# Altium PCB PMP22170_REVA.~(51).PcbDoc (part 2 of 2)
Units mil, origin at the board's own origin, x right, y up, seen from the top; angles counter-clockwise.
Board outline 4950 x 3450 mil, 2 copper layers (Top Layer, Bottom Layer), stack 62 mil thick; 75 components, 28 nets, 160 pads, 117 vias.
Unrouted connection lines stored in the file: 141.

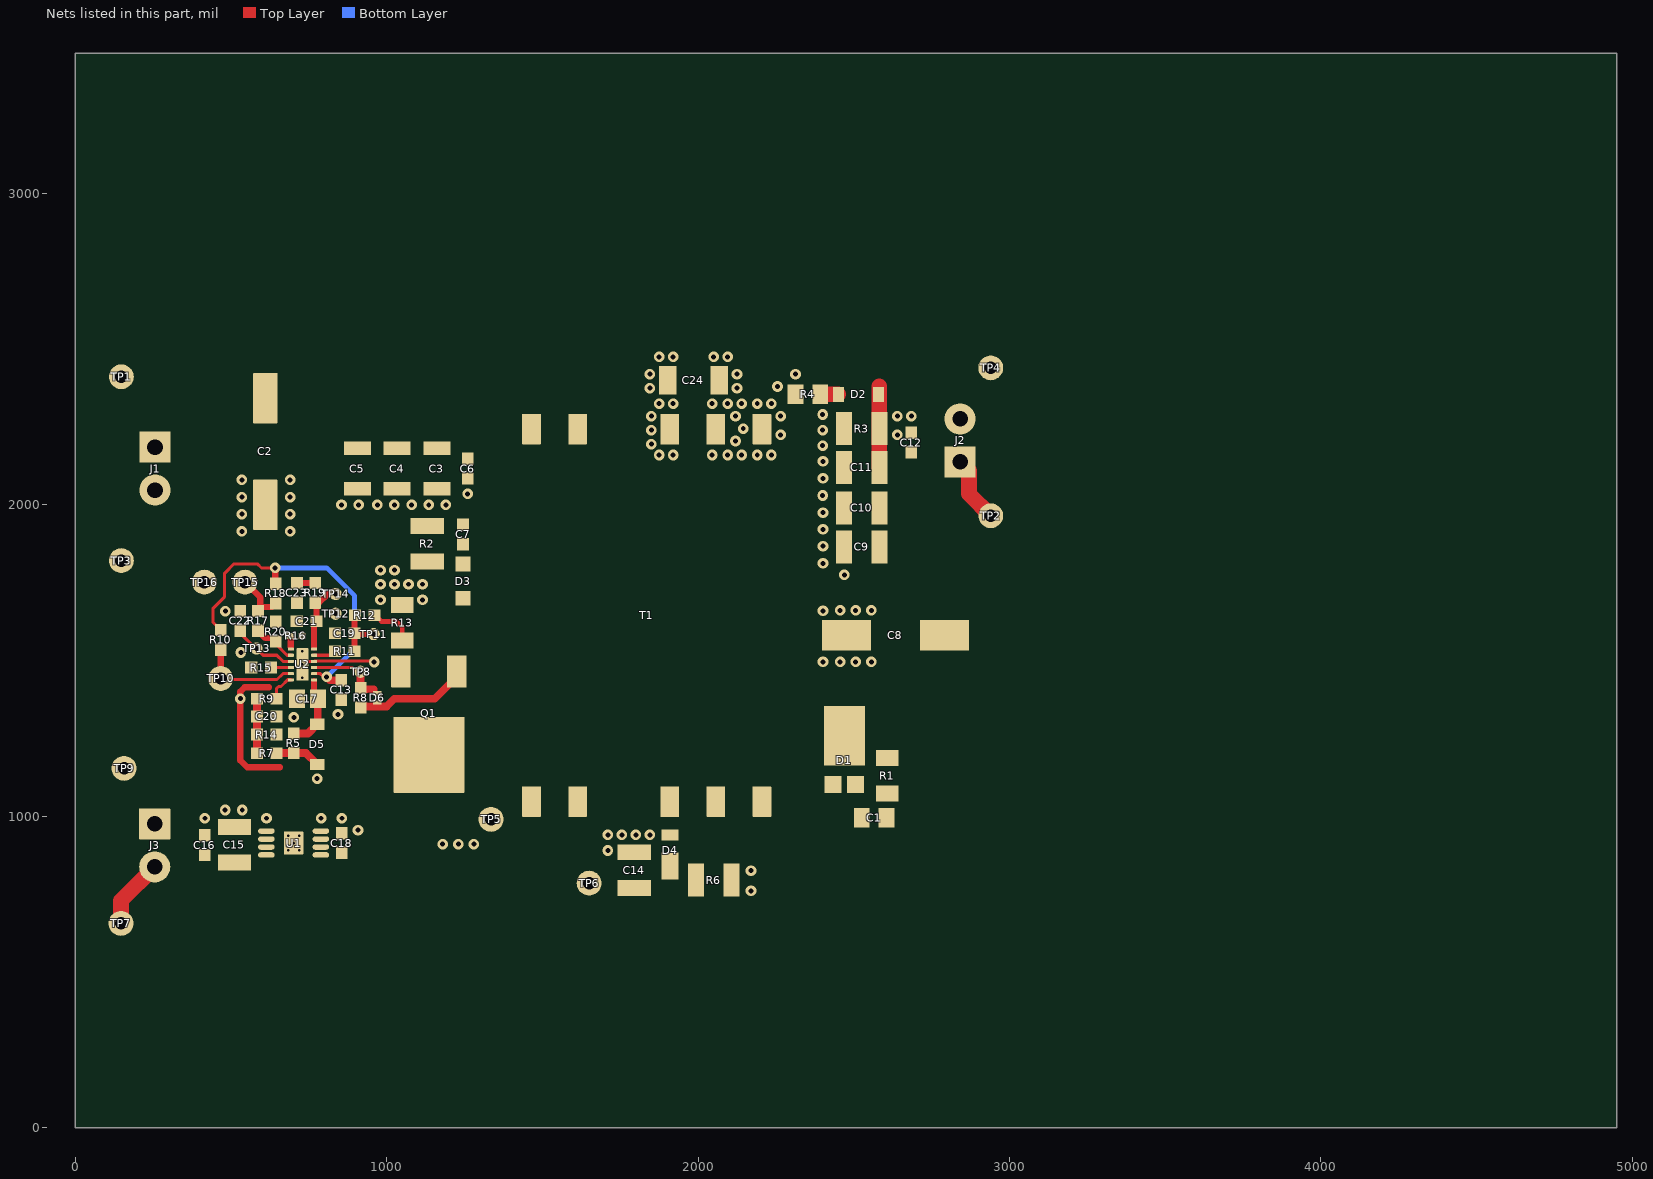
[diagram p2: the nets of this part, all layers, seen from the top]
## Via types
v1: diameter 34, hole 16, Top Layer to Bottom Layer, 109 vias
v2: diameter 19.68, hole 7.87, Top Layer to Bottom Layer, 8 vias

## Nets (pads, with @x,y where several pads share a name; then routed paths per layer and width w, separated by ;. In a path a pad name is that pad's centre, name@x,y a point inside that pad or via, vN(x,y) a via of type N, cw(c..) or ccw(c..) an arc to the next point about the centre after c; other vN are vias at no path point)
GND: C2.1 C3.2 C4.2 C5.2 C6.2 C13.2 C14.2 C15.2 C16.2 C17.2 C18.2 C19.2 C20.2 C21.2 C22.2 C23.2 C24.2 J1.2 J3.1 R6.1 R13.1 R14.1 R15.1 R16.1 R20.1 T1.9 TP3.1 TP9.1 TP12.1 TP16.1 U1.3 U1.4 U1.5 U1.6 U1.7 U1.9 U2.4 U2.13@729.43,1487.34 | length 690.3
  Top Layer w10: v2(729.43,1487.34) 739.27,1497.18 U2.4@766.83,1497.18 767.74,1498.08 956.73,1498.08 v1(959.45,1495.37)
  Top Layer w20: 621.83,1413.91 543.43,1413.91 529.91,1400.39 v1(529.91,1377.34) 529.91,1179.26 551.83,1157.34 656.83,1157.34
  other v1: 2170,760 2170,825 1710,890 1179.41,910 1230,910 1280,910 1710,940 1755,940.2 1800,940 1845,940 907.8,955.27 416.04,993.46 613.93,993.46 789.11,993.46 856.04,993.46 481.04,1020.03 536.04,1020.03 701.83,1317.34 843.57,1327.34 531.83,1525.84 835.75,1650.37 481.83,1658.71 980,1695 1115,1695 980,1745 1025,1745 1070,1745 1115,1745 980,1790 1025,1790 535,1915 690,1915 535,1970 690,1970 854.76,1999.87 909.76,1999.87 969.76,1999.87 1024.76,1999.87 1080,1999.87 1135,1999.87 1189.76,1999.87 535,2025 690,2025 1260,2035 535,2080 690,2080 1875,2160 1920,2160 1850,2195 1850,2240 1850,2285 1875,2325 1920,2325 1845,2375 1845,2420 1875,2475 1920,2475
  other v2: 683.33,890.27 718.76,890.27 701.04,913.89 683.33,937.51 718.76,937.51 729.43,1445.01 729.43,1529.66
GND2: C8.2 C9.2 C10.2 C11.2 C12.2 C24.1 J2.2 R3.1 R4.1 T1.7 T1.8 TP4.1
  other v1: 2401.22,1495.81 2456.22,1495.81 2506.22,1495.81 2556.22,1495.81 2401.22,1659.59 2456.22,1660.81 2506.22,1660.81 2556.22,1660.81 2470,1775 2401.22,1812.32 2401.22,1867.32 2401.22,1921.14 2401.22,1975 2400,2030 2401.22,2085.24 2401.22,2139.68 2045,2160 2095,2160 2140,2160 2190,2160 2235,2160 2400,2190 2120,2205 2265,2225 2640,2225 2400,2240 2145,2245 2120,2284.96 2265,2285 2640,2284.96 2685,2285 2400,2290 2045,2325 2095,2325 2140,2325 2190,2325 2235,2325 2125,2375 2255,2380 2125,2420 2312.77,2420 2050,2475 2095,2475
NetC1_1: C1.1 R1.1
NetC1_2: C1.2 D1.1 D1.2 T1.5 T1.6
NetC2_2: C2.2 C3.1 C4.1 C5.1 C6.1 C7.1 D5.2 J1.1 R2.2 R5.2 R7.2 T1.11 T1.12 TP1.1 | length 145.7
  Top Layer w25: R7.2@646.28,1202.3 646.64,1202.65 R5.2@701.83,1202.65 740.55,1202.65 D5.2@776.83,1166.37
  other v1: 776.83,1120.37
NetC7_2: C7.2 D3.1 R2.1
NetC8_1: C8.1 C9.1 C10.1 C11.1 C12.1 D1.3 D2.1 J2.1 R1.2 R3.2 TP2.1 | length 473.7
  Top Layer w50: C11.1@2582.09,2120 2582.09,2380 ; J2.1@2841.5,2137.89 2870,2109.39 2870,2035 TP2.1@2940,1965
NetC13_1: C13.1 C14.1 C18.1 D4.1 R6.2 R10.1 R18.2 TP6.1 U1.1 U1.2 U2.2 | length 1125.5
  Top Layer w10: R10.1@466.83,1597.69 442.5,1622.02 442.5,1668.42 479.45,1705.37 479.45,1780.37 509.45,1810.37 584.6,1810.37 597.63,1797.34 v1(641.83,1797.34) ; U2.2@766.83,1457.81 786.89,1457.81 797.36,1447.34 v1(806.83,1447.34)
  Top Layer w20: v1(641.83,1797.34) 641.83,1748.38 R18.2@643.33,1746.88
  Top Layer w25: v1(806.83,1447.34) 817.31,1436.86 C13.1@854.45,1436.86
  Bottom Layer w15: v1(641.83,1797.34) 807.48,1797.34 896.71,1708.1 896.71,1537.22 v1(806.83,1447.34)
NetC15_1: C15.1 C16.1 J3.2 TP7.1 U1.8 | length 226.4
  Top Layer w50: TP7.1@146.59,655.86 146.59,729.14 J3.2@254.86,837.41
NetC17_1: C17.1 D5.1 R5.1 U2.1 | length 235.8
  Top Layer w10: 766.83,1432.34 U2.1@766.83,1438.12
  Top Layer w20: 766.83,1432.34 766.83,1389.23 C17.1@778.76,1377.3
  Top Layer w25: R5.1@701.83,1265.64 747.17,1265.64 D5.1@776.83,1295.31 778.76,1297.24 C17.1@778.76,1377.3
NetC19_1: C19.1 R11.2 R12.1 TP11.1 | length 178.8
  Top Layer w20: R11.2@896.71,1529.66 C19.1@896.71,1587.34 ; R12.1@897.95,1645.37 896.71,1644.13 C19.1@896.71,1587.34 ; v1(958.29,1584.89) 899.16,1584.89 C19.1@896.71,1587.34
NetC20_1: C20.1 R7.1 R9.1 R14.2 | length 175
  Top Layer w25: R7.1@583.29,1202.3 C20.1@583.29,1320.34 R9.1@583.29,1377.34
NetC21_1: C21.1 R19.2 TP14.1 U2.6 | length 231
  Top Layer w10: U2.6@766.83,1536.55 766.83,1544.42
  Top Layer w20: 766.83,1544.42 766.83,1618.34 C21.1@774.33,1625.84 774.33,1681.84 R19.2@770.34,1685.84 782.38,1685.84 810.24,1713.7 v1(835.75,1713.7)
NetC22_1: C22.1 TP13.1 U2.9 | length 207.4
  Top Layer w10: C22.1@529.91,1595.72 529.91,1588.12 579.39,1538.63 v1(581.83,1538.63) 603.6,1516.86 647.03,1516.86 666.71,1497.18 U2.9@692.03,1497.18
NetC23_1: C23.1 R19.1 | length 58.5
  Top Layer w20: C23.1@711.83,1748.83 R19.1@770.34,1748.83
NetD2_2: D2.2 R4.2 | length 57.9
  Top Layer w50: R4.2@2392.77,2355 D2.2@2450.7,2355
NetD3_2: D3.2 Q1.2 T1.1 T1.2 TP5.1
NetD4_2: D4.2 T1.4
NetD6_1: D6.1 R8.2 TP8.1 U2.3 | length 265.8
  Top Layer w10: U2.3@766.83,1477.49 889.59,1477.49 903.17,1463.91 v1(915.97,1463.91)
  Top Layer w15: 958.29,1407.93 D6.1@967.65,1395.27
  Top Layer w25: v1(915.97,1463.91) 915.97,1413.02 R8.2@917.13,1411.86 921.07,1407.93 958.29,1407.93
NetD6_2: D6.2 Q1.1 R8.1 | length 366
  Top Layer w25: R8.1@917.13,1348.87 921.07,1352.81 1000.24,1352.81 1024.72,1377.3 1154.41,1377.3 1225.12,1448 Q1.1@1225.12,1464.97
NetQ1_3: Q1.3 R12.2 R13.2 | length 148.1
  Top Layer w15: R12.2@960.95,1645.37 970.95,1635.37 973.35,1635.37 983.35,1625.37 1032.43,1625.37 1049.45,1608.34 R13.2@1049.45,1564.09
NetR9_2: R9.2 U2.12 | length 90.3
  Top Layer w10: R9.2@646.28,1377.34 646.28,1410.45 652.5,1416.67 660.4,1416.67 681.85,1438.12 U2.12@692.03,1438.12
NetR11_1: R11.1 U2.5 | length 72.2
  Top Layer w10: U2.5@766.83,1516.86 820.93,1516.86 R11.1@833.72,1529.66
NetR15_2: R15.2 U2.10 | length 63.7
  Top Layer w10: R15.2@628.33,1477.49 U2.10@692.03,1477.49
NetR16_2: R16.2 U2.7 | length 43.8
  Top Layer w10: U2.7@692.03,1536.55 692.03,1544.41
  Top Layer w20: R16.2@688.7,1578.99 692.03,1575.66 692.03,1544.41
NetR17_1: R17.1 R18.1 TP15.1 | length 169.3
  Top Layer w20: TP15.1@544.9,1751.78 593.9,1702.79 593.9,1678.77 R17.1@600.34,1672.34 ; R17.1@586.83,1658.83 R17.1@600.34,1672.34 ; R18.1@643.33,1683.89 631.77,1672.34 R17.1@600.34,1672.34
NetR17_2: R17.2 R20.2 U2.8 | length 142.5
  Top Layer w10: R20.2@643.33,1561.27 643.33,1553.43 679.9,1516.86 U2.8@692.03,1516.86
  Top Layer w20: R17.2@586.83,1595.84 610.34,1572.34 632.27,1572.34 R20.2@643.33,1561.27
PG: R10.2 TP10.1 U2.11 | length 326.8
  Top Layer w10: TP10.1@466.83,1442.34 470.3,1438.87 647.78,1438.87 666.71,1457.81 U2.11@692.03,1457.81
  Top Layer w20: TP10.1@466.83,1442.34 R10.2@466.83,1534.7
pads on no net: U2.13@729.43,1460.37 U2.13@729.43,1514.3

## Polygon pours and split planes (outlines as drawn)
NetC8_1 on Top Layer "TOP_LAYER_NETC8_1_P046" (solid, remove dead copper, pour order 46): 2401.22,1160 2405,1163.78 2405,1430 2435,1460 2565.83,1460 2594.61,1488.78 2595,1671.22 2556.22,1710 2556.22,2163.54 2582.68,2190 2641.65,2190 2890,2190 2890,2062.24 2875,2047.24 2757.24,2047.24 2725,2015 2725,1855 2870,1710 2870,1260 2770,1160
NetC1_1 on Top Layer "TOP_LAYER_NETC1_1_P042" (solid, remove dead copper, pour order 42): 2570,950 2585,935 2636.5,935 2653.78,952.28 2653.78,1140.91 2644.66,1150.02 2580.02,1150.02 2570,1140
NetC1_2 on Top Layer "TOP_LAYER_NETC1_2_P040" (solid, remove dead copper, pour order 40): 2025,955 2045,935 2535,935 2550,950 2549.72,950.28 2549.72,1137.99 2535,1152.72 2392.28,1152.72 2341.84,1203.16 2078.14,1203.16 2025,1150.02
NetC8_1 on Top Layer "TOP_LAYER_NETC8_1_P038" (solid, remove dead copper, pour order 38): 2835,1050
NetC13_1 on Top Layer "TOP_LAYER_NETC13_1_P034" (solid, remove dead copper, pour order 34): 1940,882.4 1880,882.4 1840.63,843.03 968.6,843.03 904.43,907.2 760,907.2 760,811.83 826.83,745 2015,745 2020,750 2020,847.97 2019.82,848.15 1983.07,848.15
NetD4_2 on Top Layer "TOP_LAYER_NETD4_2_P032" (solid, remove dead copper, pour order 32): 1870.5,934.5 1870.5,969.5 1850,990 1850,1100 1860,1110 1925,1110 1940,1095 1940,925 1935,920 1885,920
GND on Top Layer "TOP_LAYER_GND_P030" (solid, remove dead copper, pour order 30): 1700,960 1665,925 1011.1,925 951.1,985 885,985 885,944.02 969.02,860 1849.25,860 1863.58,874.33 1863.58,946.69 1855,955.27 1850.27,960
GND on Top Layer "TOP_LAYER_GND_P028" (solid, remove dead copper, pour order 28): 1845,970
NetD3_2 on Top Layer "TOP_LAYER_NETD3_2_P026" (solid, remove dead copper, pour order 26): 1001.1,965 951.1,1015 951.1,1241.35 1049.75,1340 1179.24,1340 1216.57,1377.34 1260.25,1377.34 1302.91,1420 1302.91,1562.09 1220,1645 1220,1725 1675,1725 1795,1605 1795,990 1785,980 1690,980 1650.2,940.2 1024.72,940.2
NetC7_2 on Top Layer "TOP_LAYER_NETC7_2_P024" (solid, remove dead copper, pour order 24): 1076.85,1876.54 1095.31,1895 1276.73,1895 1288.39,1883.35 1288.39,1768.39 1275,1755 1150,1755 1110,1795 1076.85,1795
NetC2_2 on Top Layer "TOP_LAYER_NETC2_2_P020" (solid, remove dead copper, pour order 20): 650,2460 1760,2460 1795,2425 1795,2025 1675,1905 1076.85,1905 1075,1906.85 1075,1959.98 1206.28,1959.98 1246.17,1999.87 1282.78,1999.87 1302.91,2020 1302.91,2103.45 1290,2116.37 692.89,2116.35 649.23,2160
NetC2_2 on Top Layer "TOP_LAYER_NETC2_2_P018" (solid, remove dead copper, pour order 18): 605.53,2460.46 1620,2460.46
NetC2_2 on Top Layer "TOP_LAYER_NETC2_2_P016" (solid, remove dead copper, pour order 16): 70,2330
NetC2_2 on Top Layer "TOP_LAYER_NETC2_2_P014" (solid, remove dead copper, pour order 14): 130,2116.35 1278.52,2116.35 1278.54,2116.37 1278.54,2221.46 1250,2250 900,2250 689.54,2460.46 135.46,2460.46 100,2425 100,2145
NetQ1_3 on Top Layer "TOP_LAYER_NETQ1_3_P012" (solid, remove dead copper, pour order 12): 1092.99,1413.91 1099.45,1420.37 1099.45,1585.37 1094.45,1590.37 1005.43,1590.37 999.96,1584.89 999.45,1584.89 999.45,1422.7 1008.24,1413.91
NetQ1_3 on Top Layer "TOP_LAYER_NETQ1_3_P010" (solid, remove dead copper, pour order 10): 1045.59,1464.97
NetC15_1 on Top Layer "TOP_LAYER_NETC15_1_P008" (solid, remove dead copper, pour order 8): 642,881.6 642,812 575,745 146.59,745 146.59,883.24 169.86,906.51 546.14,906.51 564.19,888.46 634.83,888.77
NetC13_1 on Top Layer "TOP_LAYER_NETC13_1_P006" (solid, remove dead copper, pour order 6): 896.04,873.46
NetC13_1 on Top Layer "TOP_LAYER_NETC13_1_P004" (solid, remove dead copper, pour order 4): 876.04,906.22 760,906.22 760,857.41 768.96,848.46 876.04,848.46

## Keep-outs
Keep-Out Layer:
  text ".Layer_Name" at 577,-858.49 h60

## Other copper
Top Layer:
  text ".Layer_Name" at 577,-858.49 h60
Bottom Layer:
  text ".Layer_Name" at 577,-858.49 h60

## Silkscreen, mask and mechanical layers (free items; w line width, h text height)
Top Overlay:
  text "'.PRJ_Number'.PCB_Rev" at 3503.94,187.01 h108.27
  text ".Layer_Name" at 577,-858.49 h60
Bottom Overlay:
  text ".Layer_Name" at 577,-858.49 h60
Top Paste:
  text ".Layer_Name" at 577,-858.49 h60
Bottom Paste:
  text ".Layer_Name" at 577,-858.49 h60
Top Solder:
  text ".Layer_Name" at 577,-858.49 h60
  text ".Layer_Name" at 577,-858.49 h60
Bottom Solder:
  text ".Layer_Name" at 577,-858.49 h60
Drill Guide:
  text ".Layer_Name" at 577,-858.49 h60
M1 Board Outline:
  the board outline again, w10
  text ".Layer_Name" at 577,-858.49 h60
M2 Board Dimensions:
  rectangle: 0,-275 125,-150
  rectangle: 125,-400 500,-275
  lines w7: 0,-275 1000,-275 ; 125,-400 125,-150 ; 250,-400 250,-150 ; 500,-400 500,-150 ; 750,-400 750,-150 ; 0,-400 1000,-400 1000,-150 0,-150 0,-400
  text ".Layer_Name" at 577,-858.49 h60
M3 3D STEP Top:
  text ".Layer_Name" at 577,-858.49 h60
M4 3D STEP Bottom:
  text ".Layer_Name" at 577,-858.49 h60
M5 Assembly Top:
  lines w10: -292,-930.17 6308,-930.17 ; -292,-726.83 6310,-726.83 ; -292,-523.5 -292,-1133.5 3713,-1133.5 6310,-1133.5 6310,-523.5 -291.5,-523.5 -291.5,-1133.5 1284,-1133.5 ; 2173,-1133.5 2173,-523.5 ; 3440,-726.83 3440,-523.5 ; 4280,-726.83 4280,-523.5 ; 4902,-1140 4902,-937.17
  text "COMPONENTS MARKED 'DNP' SHOULD NOT BE POPULATED." at 1153.5,-318.5 h60
  text "ASSEMBLY VARIANT:" at 1153,-434 h60
  text ".VariantName" at 2189,-434 h60
  text "PCB VIEWED FROM TOP SIDE" at -228.5,-655.67 h60
  text "BOARD #:" at 2248,-655.67 h60
  text ".PRJ_Number" at 2793.5,-655.67 h60
  text "REV:" at 3638,-655.67 h60
  text ".PCB_Rev" at 3929.5,-655.67 h60
  text "SVN REV:" at 4476,-655.67 h60
  text ".VersionControl_RevNumber" at 4982,-655.67 h60
  text "TID #:" at 2248,-859 h60
  text ".TID" at 2793.5,-859 h60
  text "PLOT NAME =" at -228.5,-1064.34 h60
  text ".plot_File_Name" at 577,-1064.34 h60
  text "GENERATED    :" at 2250,-1064.34 h60
  text ".Print_Date" at 3119.5,-1064.34 h60
  text ".Print_Time" at 3848.5,-1064.34 h60
  text "TEXAS INSTRUMENTS" at 5113,-1064.34 h60
M6 Assembly Bottom:
  lines w10: -292.5,-727.33 6309.5,-727.33 ; -290.5,-930.67 6309.5,-930.67 ; 1115.5,-1140.5 1115.5,-937.67 ; 1737.5,-727.33 1737.5,-524 ; 2577.5,-727.33 2577.5,-524 ; 3844.5,-1134 3844.5,-524 ; 4733.5,-1134 6309,-1134 6309,-524 -292.5,-524 -292.5,-1134 2304.5,-1134 6309.5,-1134 6309.5,-524
  text "COMPONENTS MARKED 'DNP' SHOULD NOT BE POPULATED." at 6102,-318 h60
  text ".VariantName" at 5058,-434 h60
  text "ASSEMBLY VARIANT:" at 6097,-434 h60
  text ".VersionControl_RevNumber" at 1035.5,-656.17 h60
  text "SVN REV:" at 1541.5,-656.17 h60
  text ".PCB_Rev" at 2088,-656.17 h60
  text "REV:" at 2379.5,-656.17 h60
  text ".PRJ_Number" at 3224,-656.17 h60
  text "BOARD #:" at 3769.5,-656.17 h60
  text "PCB VIEWED FROM BOTTOM SIDE" at 6246,-656.17 h60
  text ".TID" at 3224,-859.5 h60
  text "TID #:" at 3769.5,-859.5 h60
  text "TEXAS INSTRUMENTS" at 904.5,-1064.84 h60
  text ".Print_Time" at 2169,-1064.84 h60
  text ".Print_Date" at 2898,-1064.84 h60
  text "GENERATED    :" at 3767.5,-1064.84 h60
  text ".plot_File_Name" at 5440.5,-1064.84 h60
  text "PLOT NAME =" at 6246,-1064.84 h60
M9 Title Sheet:
  drawing of 57 lines, arcs and shapes, not listed
  text "1" at 739.84,8036.5 h70
  text "2" at 3235.5,8036.5 h70
  text "3" at 5724.84,8036.5 h70
  text "4" at 8231.51,8036.5 h70
  text "5" at 10730.5,8036.5 h70
  text "6" at 13235.5,8036.5 h70
  text "A" at -416.5,6893.5 h70
  text "A" at 14383.5,6893.5 h70
  text "B" at -416.5,4513.5 h70
  text "B" at 14383.5,4513.5 h70
  text "C" at -416.5,2138.5 h70
  text "C" at 14383.5,2138.5 h70
  text "PROJECT TITLE:" at 11343.5,277.5 h45
  text ".PRJ_Title" at 11393.5,144.17 h70
  text "DESIGNED FOR:" at 11343.5,-23.5 h45
  text ".PRJ_Customer" at 11393.5,-163.5 h70
  text "D" at -416.5,-231.5 h70
  text "D" at 14383.5,-231.5 h70
  text "FILE NAME:" at 11343.5,-323.5 h45
  text ".PCB_File_Name_No_Path" at 11393.5,-443.5 h70
  text "Texas Instruments (TI) and/or its licensors do not warrant the accuracy or completeness of this specification" at 6374,-605.34 h45
  text "ENGINEER:" at 11343.5,-613.5 h45
  text "LAYOUT BY:" at 12848.5,-613.5 h45
  text "or any information contained therein. TI and/or its licensors do not warrant that this design will meet" at 6329.01,-718 h45
  text ".PRJ_Engineer" at 11393.5,-768.49 h70
  text ".PCB_Layout" at 12899,-768.49 h70
  text "the specifications, will be suitable for your application or fit for any particular purpose, or will operate in" at 6329.01,-830.67 h45
  text ".Layer_Name" at 577,-858.49 h60
  text "ALTIUM DESIGNER VERSION:" at 12848.5,-923.5 h45
  text "an implementation. TI and/or its licensors do not warrant that the design is production worthy. You should" at 6329.01,-943.33 h45
  text "completely validate and test your design implementation to confirm the system functionality for your application." at 6374,-1056 h45
  text ".print_Scale" at 11393.5,-1056.83 h70
  text ".Application_BuildNumber" at 12899,-1056.83 h70
  text "1" at 739.84,-1263.5 h70
  text "2" at 3235.5,-1263.5 h70
  text "3" at 5724.84,-1263.5 h70
  text "4" at 8231.51,-1263.5 h70
  text "5" at 10730.5,-1263.5 h70
  text "6" at 13235.5,-1263.5 h70
M10 Fab Notes:
  drawing of 189 lines, arcs and shapes, not listed
  text "DESIGN INFORMATION" at 12382.02,6356.17 h60
  text "MIN. TRACK WIDTH:" at 11737.46,6224.05 h60
  text "8" at 12833.7,6224.05 h60
  text "MIL" at 12988.46,6224.05 h60
  text "MIN. CLEARANCE:" at 11737.46,6099.92 h60
  text "0.2" at 12773.7,6099.93 h60
  text "mm" at 12988.46,6099.92 h60
  text "MIN. VIA PAD SIZE:" at 11737.46,5975.8 h60
  text "24" at 12803.71,5975.8 h60
  text "MIL" at 12988.46,5975.8 h60
  text "0.05mm (2MIL)" at 12432.46,5845.9 h60
  text "MINIMUM ANNULAR RING" at 11408.23,5837.67 h60
  text "EXTERNAL" at 13140.46,5837.67 h60
  text "PER" at 11608.23,5727.55 h60
  text "IPC-D-275 CLASS 2 LEVEL C" at 11828.23,5727.54 h60
  text "MIL, HOLES" at 13316.46,5627.07 h60
  text "+/-" at 12924,5618.48 h60
  text "+/-" at 13778,5618.48 h60
  text "REGISTRATION TOLERANCES:" at 11408.23,5617.42 h60
  text "METAL" at 12608,5617.42 h60
  text "5" at 13184.2,5617.42 h60
  text "3" at 14017.2,5617.42 h60
  text "MIL" at 14133.46,5617.42 h60
  text "HOLE SIZE TOLERANCE (UNLESS OTHERWISE SPECIFIED):" at 11408.23,5519.1 h60
  text "+/-" at 13778,5516.23 h60
  text "3" at 14017.2,5515.17 h60
  text "MIL" at 14133.46,5515.17 h60
  text "MATERIAL:" at 11333.46,5377.52 h60
  text "FR-4 High Tg" at 12319.9,5249 h60
  text "X" at 12175.46,5241.01 h60
  text "FR-408" at 11754.46,5236.49 h60
  text "OTHER" at 13242.46,5236.49 h60
  text "62 MIL (1.6mm) +/-10%" at 12074.56,5093.46 h60
  text "X" at 11954.46,5091.01 h60
  text "THICKNESS:" at 11408.23,5085.24 h60
  text "OTHER" at 13359.46,5085.24 h60
  text "TOLERANCE:" at 11408.23,4946.92 h60
  text "X" at 12256.46,4946.92 h60
  text "ANSI IPC-6012 TYPE 3 CLASS 2" at 12434.48,4946.92 h60
  text "OTHER +/-" at 12434.46,4802.73 h60
  text "BOW & TWIST:" at 11408.23,4657.54 h60
  text "X" at 12256.46,4657.54 h60
  text "ANSI IPC-6012 TYPE 3 CLASS 2" at 12434.48,4657.54 h60
  text "OTHER +/-" at 12434.46,4510.85 h60
  text "DRILLING:" at 11333.46,4380.23 h60
  text "NC_DRILL FILES" at 13094.46,4275.04 h60
  text "REFERENCE:" at 11408.23,4271.1 h60
  text "X" at 12065.46,4271.01 h60
  text "AS SHOWN" at 12243.46,4271.1 h60
  text "X" at 12966.46,4271.1 h60
  text "OTHER" at 13392.46,4128.85 h60
  text "PTH COPPER THICKNESS:" at 11407.91,4125.32 h60
  text "X" at 12547.14,4125.32 h60
  text "20-30 um" at 12675.14,4125.32 h60
  text "BOARD FINISH:" at 11333.46,3977.73 h60
  text "SILKSCREEN:" at 11488.68,3867.6 h60
  text "X" at 12446.46,3867.6 h60
  text "TOP" at 12563.46,3867.6 h60
  text "X" at 12956.46,3867.6 h60
  text "BOTTOM" at 13074.46,3867.6 h60
  text "SILKSCREEN COLOR:" at 11488.68,3712.41 h60
  text "X" at 12445.46,3712.41 h60
  text "WHITE" at 12563.46,3712.41 h60
  text "OTHER" at 13074.46,3712.41 h60
  text "X" at 12576.46,3568.96 h60
  text "GREEN" at 12694.46,3568.96 h60
  text "OTHER" at 13312.46,3568.96 h60
  text "SOLDER RESIST COLOR:" at 11488.68,3562.1 h60
  text "X" at 12576.46,3414.71 h60
  text "MATTE" at 12694.46,3414.71 h60
  text "SEMI-GLOSS" at 13312,3414.07 h60
  text "IMMERSION GOLD (ENIG)" at 12394.46,3241.94 h60
  text "ENEPIG" at 13732,3234.72 h60
  text "SURFACE FINISH:" at 11333.46,3233.72 h60
  text "X" at 12216.46,3233.72 h60
  text "IMM. TIN/SILVER OR EQUIV" at 11663,3096.4 h60
  text "OTHER" at 13094.46,3092.47 h60
  text "ARRAY/PANEL:" at 11333.46,2937.09 h60
  text "CUT AND TRIM PER M1 BOARD OUTLINE" at 12394.46,2928.87 h60
  text "N.C. ROUTE" at 12394.46,2792.9 h60
  text "X" at 13082.46,2792.9 h60
  text "V. SCORE" at 13260.46,2792.9 h60
  text "CERTIFICATION:" at 11333.46,2663.77 h60
  text "MATERIALS AND WORKMANSHIP FOR ALL PCBS" at 12058.46,2663.77 h60
  text "TO MEET OR EXCEED THE REQUIREMENTS OF:" at 12058.46,2569.71 h60
  text "X" at 11695.97,2441.08 h60
  text "ANSI IPC-A-600F CLASS ->" at 11823.96,2441.08 h60
  text "X" at 13471.97,2441.08 h60
  text "2" at 13581.96,2441.08 h60
  text "1" at 13266.96,2439.58 h60
  text "3" at 13935.96,2439.58 h60
  text "X" at 12507.97,2293.39 h60
  text "RoHS" at 12635.96,2293.39 h60
  text "OTHER" at 13280.36,2293.39 h60
  text "PER ORDER" at 13677.42,2293.39 h60
  text "ALL BOARDS MUST MEET OR EXCEED UL94-V0 REQUIREMENTS." at 11361,2139.57 h60
  text "PCB MUST BEAR THE UL94V-0 UL REGISTERED MATERIAL ID NUMBER" at 11361,2023.5 h60
  text "ADDITIONAL REQUIREMENTS:" at 11333.46,1854.08 h60
  text "MICROSECTION:" at 11408.23,1746.95 h60
  text "YES" at 12313.96,1746.95 h60
  text "REQUIRED" at 13175.46,1602.62 h60
  text "BARE BOARD ELEC. TEST:" at 11408.23,1599.76 h60
  text "NONE" at 12713.96,1599.76 h60
  text "X" at 13057.46,1599.76 h60
  text "PER ORDER" at 13767.46,1599.76 h60
  text "XX MIL VIAS REQUIRE NON-CONDUCTIVE FILL AND PLANARIZE" at 11576.38,1394.82 h59
  text "XX MIL VIAS REQUIRE CONDUCTIVE FILL AND PLANARIZE" at 11584.38,1290.84 h60
  text "OUTER XX MIL TRACES REQUIRE 50 OHM SINGLE-ENDED IMPEDANCE" at 11583.39,1127.46 h58
  text "LAYER 2 & 3 (INNER LAYERS) XX MIL WIDE, XX MIL SPACE / TRACES REQUIRE 100 OHM DIFFERENTIAL IMPEDANCE" at 11575.39,891.74 h60
  text ".Layer_Name" at 577,-858.49 h60
M11 Gerber Information:
  lines w10: -292,-930.17 6308,-930.17 ; -292,-726.83 6310,-726.83 ; -292,-523.5 -292,-1133.5 3713,-1133.5 6310,-1133.5 6310,-523.5 -291.5,-523.5 -291.5,-1133.5 1284,-1133.5 ; 2173,-1133.5 2173,-523.5 ; 3440,-726.83 3440,-523.5 ; 4280,-726.83 4280,-523.5 ; 4902,-1140 4902,-937.17
  text "ALL ARTWORK VIEWED FROM TOP SIDE" at -228.5,-655.67 h60
  text "BOARD #:" at 2248,-655.67 h60
  text ".PRJ_Number" at 2793.5,-655.67 h60
  text "REV:" at 3638,-655.67 h60
  text ".PCB_Rev" at 3929.5,-655.67 h60
  text "SVN REV:" at 4476,-655.67 h60
  text ".VersionControl_RevNumber" at 4982,-655.67 h60
  text "LAYER NAME =" at -228.5,-858.49 h60
  text "TID #:" at 2248,-859 h60
  text ".TID" at 2793.5,-859 h60
  text "PLOT NAME =" at -228.5,-1064.34 h60
  text ".plot_File_Name" at 577,-1064.34 h60
  text "GENERATED    :" at 2250,-1064.34 h60
  text ".Print_Date" at 3119.5,-1064.34 h60
  text ".Print_Time" at 3848.5,-1064.34 h60
  text "TEXAS INSTRUMENTS" at 5113,-1064.34 h60
M12 Stackup:
  drawing of 191 lines, arcs and shapes, not listed
  text "Layer" at 9811.59,7784.94 h60
  text "Name" at 10221.51,7784.94 h60
  text "Material" at 11151.25,7784.94 h60
  text "Thickness" at 12011.02,7784.94 h60
  text "Constant" at 12660.85,7784.94 h60
  text "Board Layer Stack" at 13230.71,7784.94 h60
  text "1" at 9811.59,7664.94 h60
  text "Top Overlay" at 10221.51,7664.94 h60
  text "2" at 9811.59,7544.94 h60
  text "Top Solder" at 10221.51,7544.94 h60
  text "Solder Resist" at 11151.25,7544.94 h60
  text "0.40mil" at 12011.02,7544.94 h60
  text "3.5" at 12660.85,7544.94 h60
  text "3" at 9811.59,7424.94 h60
  text "Top Layer" at 10221.51,7424.94 h60
  text "Copper" at 11151.25,7424.94 h60
  text "1.40mil" at 12011.02,7424.94 h60
  text "4" at 9811.59,7304.94 h60
  text "Dielectric1" at 10221.51,7304.94 h60
  text "FR-4" at 11151.25,7304.94 h60
  text "59.20mil" at 12011.02,7304.94 h60
  text "4.8" at 12660.85,7304.94 h60
  text "5" at 9811.59,7184.94 h60
  text "Bottom Layer" at 10221.51,7184.94 h60
  text "Copper" at 11151.25,7184.94 h60
  text "1.40mil" at 12011.02,7184.94 h60
  text "6" at 9811.59,7064.94 h60
  text "Bottom Solder" at 10221.51,7064.94 h60
  text "Solder Resist" at 11151.25,7064.94 h60
  text "0.40mil" at 12011.02,7064.94 h60
  text "3.5" at 12660.85,7064.94 h60
  text "7" at 9811.59,6944.94 h60
  text "Bottom Overlay" at 10221.51,6944.94 h60
  text ".Layer_Name" at 577,-858.49 h60
M13 Component Bodies Top:
  text ".Layer_Name" at 577,-858.49 h60
M14 Component Bodies Bottom:
  text ".Layer_Name" at 577,-858.49 h60
M15 Courtyards Top:
  text ".Layer_Name" at 577,-858.49 h60
M16 Courtyards Bottom:
  text ".Layer_Name" at 577,-858.49 h60
Drill Drawing:
  circle w10: c5363.72,3195.96 r27.63
  lines w10: 5336.09,2974.95 5391.34,2974.95 5363.72,2919.7 5336.09,2974.95 ; 5336.09,3044.02 5391.34,3044.02 5391.34,3099.27 5336.09,3099.27 5336.09,3044.02 ; 5336.09,3306.47 5349.9,3306.47 5363.72,3292.66 5377.53,3306.47 5391.34,3306.47 5377.53,3320.28 5391.34,3334.1 5377.53,3334.1 5363.72,3347.91 5349.9,3334.1 5336.09,3334.1 5349.9,3320.28 5336.09,3306.47
  lines w12: 5286,2882.4 8517.49,2882.4 ; 5286,3379.68 8517.49,3379.68 ; 5623.86,2758.08 5623.86,3504 ; 5955.86,2758.08 5955.86,3504 ; 6592.43,2758.08 6592.43,3504 ; 6851.57,2758.08 6851.57,3504 ; 7226.72,2758.08 7226.72,3504 ; 7951.05,2758.08 7951.05,3504 ; 5286,2758.08 8517.49,2758.08 8517.49,3504 5286,3504 5286,2758.08
  text "Symbol" at 5360.59,3416.98 h72
  text "Quantity" at 5661.16,3416.98 h72
  text "Finished Hole Size" at 5993.16,3416.98 h72
  text "Plated" at 6629.72,3416.98 h72
  text "Hole Type" at 6888.86,3416.98 h72
  text "Drill Layer Pair" at 7264.02,3416.98 h72
  text "Hole Tolerance" at 7988.35,3416.98 h72
  text "8" at 5661.16,3292.66 h60
  text "7.87mil (0.200mm)" at 5993.16,3292.66 h60
  text "PTH" at 6629.72,3292.66 h60
  text "Round" at 6888.86,3292.66 h60
  text "Top Layer - Bottom Layer" at 7264.02,3292.66 h60
  text "109" at 5661.16,3168.34 h60
  text "16.00mil (0.406mm)" at 5993.16,3168.34 h60
  text "PTH" at 6629.72,3168.34 h60
  text "Round" at 6888.86,3168.34 h60
  text "Top Layer - Bottom Layer" at 7264.02,3168.34 h60
  text "11" at 5661.16,3044.02 h60
  text "40.00mil (1.016mm)" at 5993.16,3044.02 h60
  text "PTH" at 6629.72,3044.02 h60
  text "Round" at 6888.86,3044.02 h60
  text "Top Layer - Bottom Layer" at 7264.02,3044.02 h60
  text "6" at 5661.16,2919.7 h60
  text "50.00mil (1.270mm)" at 5993.16,2919.7 h60
  text "PTH" at 6629.72,2919.7 h60
  text "Round" at 6888.86,2919.7 h60
  text "Top Layer - Bottom Layer" at 7264.02,2919.7 h60
  text "134 Total" at 5661.16,2795.38 h60
  text ".Layer_Name" at 577,-858.49 h60
M17 Embedded Cavity:
  text ".Layer_Name" at 577,-858.49 h60
M18 Embedded Assembly:
  text ".Layer_Name" at 577,-858.49 h60
M19 Embedded Keepout:
  text ".Layer_Name" at 577,-858.49 h60

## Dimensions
0,-400 to 1000,-400 on M2 Board Dimensions
0,0 to 0,3450 on M2 Board Dimensions
0,0 to 4950,0 on M2 Board Dimensions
